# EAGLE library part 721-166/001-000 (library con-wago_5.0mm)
Serie 721, Stiftleiste mit geraden Einlötstiften / Series 721, Male connector with straight solder pins Polzahl / Pole No.: 6 Rastermaß / Pitch: 5 mm Bemessungsspannung / Rated Voltage: 320 V Nennstrom / Nominal Current: 16 A Lötstiftlänge: / Solder Pin Length: 5 mm Farbe / Color: lichtgrau / light gray Stand: 01.01.2012. Die jeweils aktuellen Daten zu diesem Artikel finden Sie in unserem Produktkatalog, den Sie unter www.wago.com einsehen können. As of: 01/01/2012. Please find the newest data for this article in our product catalogue, which can be viewed under www.wago.com.

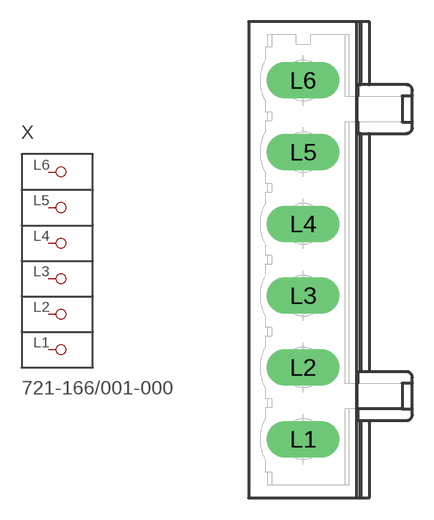
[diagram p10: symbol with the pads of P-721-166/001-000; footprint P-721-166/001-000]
Designator prefix X

## 721-166/001-000  [P-721-166/001-000]
L1  P1
L2  P2
L3  P3
L4  P4
L5  P5
L6  P6

## Footprint P-721-166/001-000 (pad centres in mm)
drill 1.7 long: L1 -1.9,-12.5; L2 -1.9,-7.5; L3 -1.9,-2.5; L4 -1.9,2.5; L5 -1.9,7.5; L6 -1.9,12.5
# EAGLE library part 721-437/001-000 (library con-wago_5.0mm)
Serie 721, Stiftleiste mit abgewinkelten Einlötstiften / Series 721, Male connector with angled solder pins Polzahl / Pole No.: 7 Rastermaß / Pitch: 5 mm Bemessungsspannung / Rated Voltage: 320 V Nennstrom / Nominal Current: 12 A Lötstiftlänge: / Solder Pin Length: 3.8 mm Farbe / Color: lichtgrau / light gray Stand: 01.01.2012. Die jeweils aktuellen Daten zu diesem Artikel finden Sie in unserem Produktkatalog, den Sie unter www.wago.com einsehen können. As of: 01/01/2012. Please find the newest data for this article in our product catalogue, which can be viewed under www.wago.com.

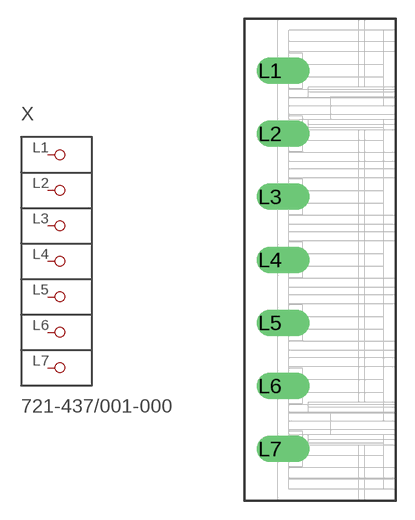
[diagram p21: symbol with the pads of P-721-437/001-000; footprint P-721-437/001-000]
Designator prefix X

## 721-437/001-000  [P-721-437/001-000]
L1  P1
L2  P2
L3  P3
L4  P4
L5  P5
L6  P6
L7  P7

## Footprint P-721-437/001-000 (pad centres in mm)
drill 1.4 offset: L1 -4,15; L2 -4,10; L3 -4,5; L4 -4,0; L5 -4,-5; L6 -4,-10; L7 -4,-15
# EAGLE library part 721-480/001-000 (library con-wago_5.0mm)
Serie 721, Stiftleiste mit abgewinkelten Einlötstiften / Series 721, Male connector with angled solder pins Polzahl / Pole No.: 20 Rastermaß / Pitch: 5 mm Bemessungsspannung / Rated Voltage: 320 V Nennstrom / Nominal Current: 16 A Lötstiftlänge: / Solder Pin Length: 3.8 mm Farbe / Color: lichtgrau / light gray Stand: 01.01.2012. Die jeweils aktuellen Daten zu diesem Artikel finden Sie in unserem Produktkatalog, den Sie unter www.wago.com einsehen können. As of: 01/01/2012. Please find the newest data for this article in our product catalogue, which can be viewed under www.wago.com.

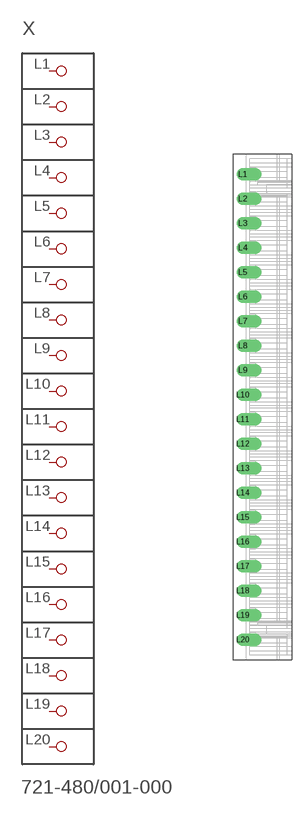
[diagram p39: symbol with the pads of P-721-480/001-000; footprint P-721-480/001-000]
Designator prefix X

## 721-480/001-000  [P-721-480/001-000]
L1  P1
L2  P2
L3  P3
L4  P4
L5  P5
L6  P6
L7  P7
L8  P8
L9  P9
L10  P10
L11  P11
L12  P12
L13  P13
L14  P14
L15  P15
L16  P16
L17  P17
L18  P18
L19  P19
L20  P20

## Footprint P-721-480/001-000 (pad centres in mm)
drill 1.7 offset: L1 -4,47.5; L2 -4,42.5; L3 -4,37.5; L4 -4,32.5; L5 -4,27.5; L6 -4,22.5; L7 -4,17.5; L8 -4,12.5; L9 -4,7.5; L10 -4,2.5; L11 -4,-2.5; L12 -4,-7.5; L13 -4,-12.5; L14 -4,-17.5; L15 -4,-22.5; L16 -4,-27.5; L17 -4,-32.5; L18 -4,-37.5; L19 -4,-42.5; L20 -4,-47.5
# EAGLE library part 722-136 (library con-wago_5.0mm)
Serie 722, Federleiste mit geraden Einlötstiften / Series 722, Female connector with straight solder pins Polzahl / Pole No.: 6 Rastermaß / Pitch: 5 mm Bemessungsspannung / Rated Voltage: 320 V Nennstrom / Nominal Current: 12 A Lötstiftlänge: / Solder Pin Length: 5 mm Farbe / Color: lichtgrau / light gray Stand: 01.01.2012. Die jeweils aktuellen Daten zu diesem Artikel finden Sie in unserem Produktkatalog, den Sie unter www.wago.com einsehen können. As of: 01/01/2012. Please find the newest data for this article in our product catalogue, which can be viewed under www.wago.com.

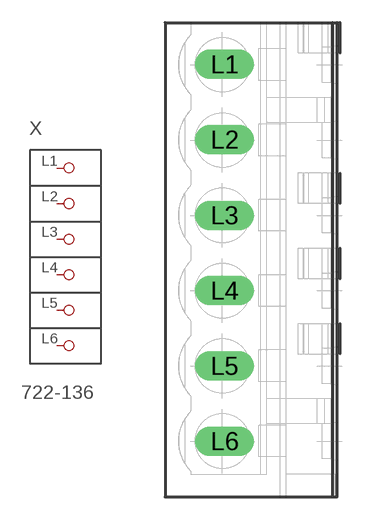
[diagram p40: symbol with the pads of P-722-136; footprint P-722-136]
Designator prefix X

## 722-136  [P-722-136]
L1  P1
L2  P2
L3  P3
L4  P4
L5  P5
L6  P6

## Footprint P-722-136 (pad centres in mm)
drill 1.3 long: L1 -1.923,12.975; L2 -1.923,7.975; L3 -1.923,2.95; L4 -1.923,-2.05; L5 -1.923,-7.05; L6 -1.923,-12.05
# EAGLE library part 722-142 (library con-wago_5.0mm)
Serie 722, Federleiste mit geraden Einlötstiften / Series 722, Female connector with straight solder pins Polzahl / Pole No.: 12 Rastermaß / Pitch: 5 mm Bemessungsspannung / Rated Voltage: 320 V Nennstrom / Nominal Current: 12 A Lötstiftlänge: / Solder Pin Length: 5 mm Farbe / Color: lichtgrau / light gray Stand: 01.01.2012. Die jeweils aktuellen Daten zu diesem Artikel finden Sie in unserem Produktkatalog, den Sie unter www.wago.com einsehen können. As of: 01/01/2012. Please find the newest data for this article in our product catalogue, which can be viewed under www.wago.com.

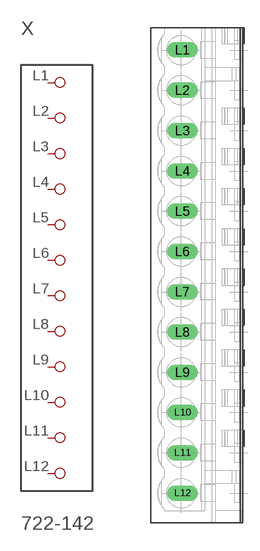
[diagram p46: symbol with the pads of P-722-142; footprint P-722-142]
Designator prefix X

## 722-142  [P-722-142]
L1  P1
L2  P2
L3  P3
L4  P4
L5  P5
L6  P6
L7  P7
L8  P8
L9  P9
L10  P10
L11  P11
L12  P12

## Footprint P-722-142 (pad centres in mm)
drill 1.3 long: L1 -2.068,27.975; L2 -2.068,22.975; L3 -2.068,17.95; L4 -2.068,12.95; L5 -2.068,7.95; L6 -2.068,2.95; L7 -2.068,-2.05; L8 -2.068,-7.05; L9 -2.068,-12.05; L10 -2.068,-17.05; L11 -2.068,-22.05; L12 -2.068,-27.05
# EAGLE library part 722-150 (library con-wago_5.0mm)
Serie 722, Federleiste mit geraden Einlötstiften / Series 722, Female connector with straight solder pins Polzahl / Pole No.: 20 Rastermaß / Pitch: 5 mm Bemessungsspannung / Rated Voltage: 320 V Nennstrom / Nominal Current: 12 A Lötstiftlänge: / Solder Pin Length: 5 mm Farbe / Color: lichtgrau / light gray Stand: 01.01.2012. Die jeweils aktuellen Daten zu diesem Artikel finden Sie in unserem Produktkatalog, den Sie unter www.wago.com einsehen können. As of: 01/01/2012. Please find the newest data for this article in our product catalogue, which can be viewed under www.wago.com.

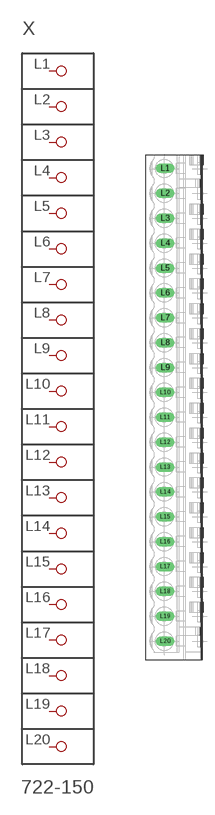
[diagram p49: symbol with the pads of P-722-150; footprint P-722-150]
Designator prefix X

## 722-150  [P-722-150]
L1  P1
L2  P2
L3  P3
L4  P4
L5  P5
L6  P6
L7  P7
L8  P8
L9  P9
L10  P10
L11  P11
L12  P12
L13  P13
L14  P14
L15  P15
L16  P16
L17  P17
L18  P18
L19  P19
L20  P20

## Footprint P-722-150 (pad centres in mm)
drill 1.3 long: L1 -2.265,47.96; L2 -2.265,42.96; L3 -2.265,37.935; L4 -2.265,32.935; L5 -2.265,27.935; L6 -2.265,22.935; L7 -2.265,17.935; L8 -2.265,12.935; L9 -2.265,7.935; L10 -2.265,2.935; L11 -2.265,-2.065; L12 -2.265,-7.065; L13 -2.265,-12.065; L14 -2.265,-17.065; L15 -2.265,-22.065; L16 -2.265,-27.065; L17 -2.265,-32.065; L18 -2.265,-37.065; L19 -2.265,-42.065; L20 -2.265,-47.065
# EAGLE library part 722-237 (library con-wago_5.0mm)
Serie 722, Federleiste mit abgewinkelten Einlötstiften / Series 722, Female connector with angled solder pins Polzahl / Pole No.: 7 Rastermaß / Pitch: 5 mm Bemessungsspannung / Rated Voltage: 320 V Nennstrom / Nominal Current: 12 A Lötstiftlänge: / Solder Pin Length: 5 mm Farbe / Color: lichtgrau / light gray Stand: 01.01.2012. Die jeweils aktuellen Daten zu diesem Artikel finden Sie in unserem Produktkatalog, den Sie unter www.wago.com einsehen können. As of: 01/01/2012. Please find the newest data for this article in our product catalogue, which can be viewed under www.wago.com.

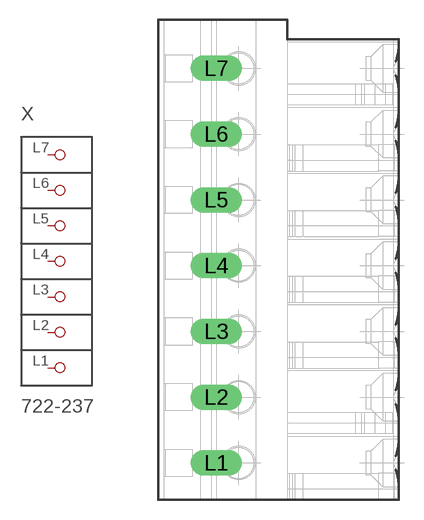
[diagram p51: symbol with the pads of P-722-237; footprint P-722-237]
Designator prefix X

## 722-237  [P-722-237]
L1  P1
L2  P2
L3  P3
L4  P4
L5  P5
L6  P6
L7  P7

## Footprint P-722-237 (pad centres in mm)
drill 1.3 long: L1 -4.939,-15.45; L2 -4.939,-10.45; L3 -4.939,-5.45; L4 -4.939,-0.45; L5 -4.939,4.55; L6 -4.939,9.55; L7 -4.939,14.55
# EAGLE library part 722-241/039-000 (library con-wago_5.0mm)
Serie 722, Federleiste mit Verriegelungsklinken / Series 722, Female connector with locking levers Polzahl / Pole No.: 11 Bemessungsspannung / Rated Voltage: 320 V Nennstrom / Nominal Current: 12 A Lötstiftlänge: / Solder Pin Length: 5 mm Farbe / Color: lichtgrau / light gray Stand: 01.01.2012. Die jeweils aktuellen Daten zu diesem Artikel finden Sie in unserem Produktkatalog, den Sie unter www.wago.com einsehen können. As of: 01/01/2012. Please find the newest data for this article in our product catalogue, which can be viewed under www.wago.com.

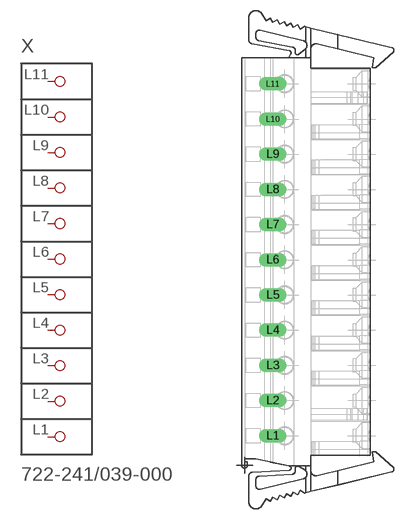
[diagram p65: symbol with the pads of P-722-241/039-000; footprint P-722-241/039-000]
Designator prefix X

## 722-241/039-000  [P-722-241/039-000]
L1  P1
L2  P2
L3  P3
L4  P4
L5  P5
L6  P6
L7  P7
L8  P8
L9  P9
L10  P10
L11  P11

## Footprint P-722-241/039-000 (pad centres in mm)
drill 1.3 long: L1 -6.03,-25; L2 -6.03,-20; L3 -6.03,-15; L4 -6.03,-10; L5 -6.03,-5; L6 -6.03,0; L7 -6.03,5; L8 -6.03,10; L9 -6.03,15; L10 -6.03,20; L11 -6.03,25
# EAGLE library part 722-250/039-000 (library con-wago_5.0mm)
Serie 722, Federleiste mit Verriegelungsklinken / Series 722, Female connector with locking levers Polzahl / Pole No.: 20 Lötstiftlänge: / Solder Pin Length: 5 mm Farbe / Color: lichtgrau / light gray Stand: 01.01.2012. Die jeweils aktuellen Daten zu diesem Artikel finden Sie in unserem Produktkatalog, den Sie unter www.wago.com einsehen können. As of: 01/01/2012. Please find the newest data for this article in our product catalogue, which can be viewed under www.wago.com.

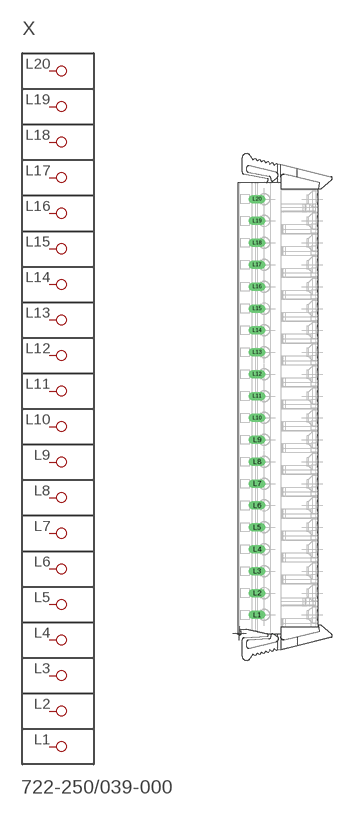
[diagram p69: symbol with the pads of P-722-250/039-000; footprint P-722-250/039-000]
Designator prefix X

## 722-250/039-000  [P-722-250/039-000]
L1  P1
L2  P2
L3  P3
L4  P4
L5  P5
L6  P6
L7  P7
L8  P8
L9  P9
L10  P10
L11  P11
L12  P12
L13  P13
L14  P14
L15  P15
L16  P16
L17  P17
L18  P18
L19  P19
L20  P20

## Footprint P-722-250/039-000 (pad centres in mm)
drill 1.3 long: L1 -5.811,-47.5; L2 -5.811,-42.5; L3 -5.811,-37.5; L4 -5.811,-32.5; L5 -5.811,-27.5; L6 -5.811,-22.5; L7 -5.811,-17.5; L8 -5.811,-12.5; L9 -5.811,-7.5; L10 -5.811,-2.5; L11 -5.811,2.5; L12 -5.811,7.5; L13 -5.811,12.5; L14 -5.811,17.5; L15 -5.811,22.5; L16 -5.811,27.5; L17 -5.811,32.5; L18 -5.811,37.5; L19 -5.811,42.5; L20 -5.811,47.5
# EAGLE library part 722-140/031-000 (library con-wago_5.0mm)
Serie 722, Federleiste mit Durchführungsflanschen / Series 722, Female connector with feedthrough flanges Polzahl / Pole No.: 10 Bemessungsspannung / Rated Voltage: 250 V Nennstrom / Nominal Current: 12 A Lötstiftlänge: / Solder Pin Length: 5 mm Farbe / Color: xxxx / xxxx Stand: 01.01.2012. Die jeweils aktuellen Daten zu diesem Artikel finden Sie in unserem Produktkatalog, den Sie unter www.wago.com einsehen können. As of: 01/01/2012. Please find the newest data for this article in our product catalogue, which can be viewed under www.wago.com.

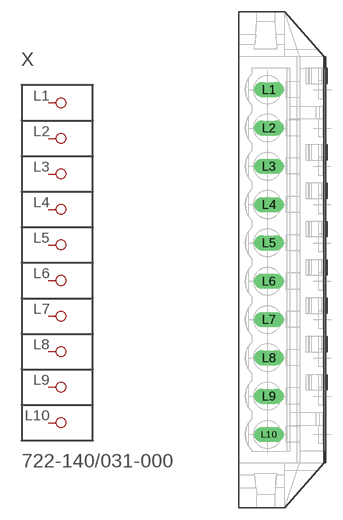
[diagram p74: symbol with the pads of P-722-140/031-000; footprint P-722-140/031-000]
Designator prefix X

## 722-140/031-000  [P-722-140/031-000]
L1  P1
L2  P2
L3  P3
L4  P4
L5  P5
L6  P6
L7  P7
L8  P8
L9  P9
L10  P10

## Footprint P-722-140/031-000 (pad centres in mm)
drill 1.3 long: L1 -2.085,22.2; L2 -2.085,17.2; L3 -2.085,12.2; L4 -2.085,7.2; L5 -2.085,2.2; L6 -2.085,-2.8; L7 -2.085,-7.8; L8 -2.085,-12.8; L9 -2.085,-17.8; L10 -2.085,-22.8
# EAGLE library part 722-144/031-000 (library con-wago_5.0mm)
Serie 722, Federleiste mit Durchführungsflanschen / Series 722, Female connector with feedthrough flanges Polzahl / Pole No.: 14 Bemessungsspannung / Rated Voltage: 250 V Nennstrom / Nominal Current: 12 A Lötstiftlänge: / Solder Pin Length: 5 mm Farbe / Color: xxxx / xxxx Stand: 01.01.2012. Die jeweils aktuellen Daten zu diesem Artikel finden Sie in unserem Produktkatalog, den Sie unter www.wago.com einsehen können. As of: 01/01/2012. Please find the newest data for this article in our product catalogue, which can be viewed under www.wago.com.

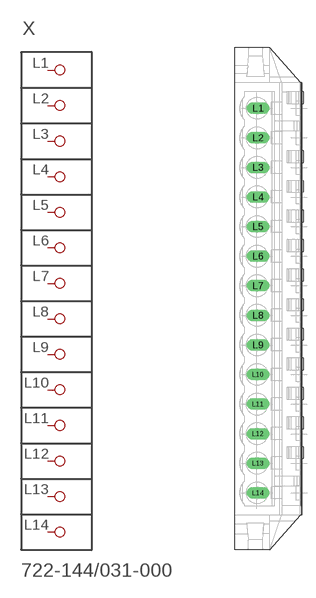
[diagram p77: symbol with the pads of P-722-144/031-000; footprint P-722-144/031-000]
Designator prefix X

## 722-144/031-000  [P-722-144/031-000]
L1  P1
L2  P2
L3  P3
L4  P4
L5  P5
L6  P6
L7  P7
L8  P8
L9  P9
L10  P10
L11  P11
L12  P12
L13  P13
L14  P14

## Footprint P-722-144/031-000 (pad centres in mm)
drill 1.3 long: L1 -2.182,32.2; L2 -2.182,27.2; L3 -2.182,22.2; L4 -2.182,17.2; L5 -2.182,12.2; L6 -2.182,7.2; L7 -2.182,2.2; L8 -2.182,-2.8; L9 -2.182,-7.8; L10 -2.182,-12.8; L11 -2.182,-17.8; L12 -2.182,-22.8; L13 -2.182,-27.8; L14 -2.182,-32.8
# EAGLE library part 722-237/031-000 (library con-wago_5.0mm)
Serie 722, Federleiste mit Durchführungsflanschen / Series 722, Female connector with feedthrough flanges Polzahl / Pole No.: 7 Rastermaß / Pitch: 5 mm Bemessungsspannung / Rated Voltage: 320 V Nennstrom / Nominal Current: 12 A Lötstiftlänge: / Solder Pin Length: 5 mm Farbe / Color: lichtgrau / light gray Stand: 01.01.2012. Die jeweils aktuellen Daten zu diesem Artikel finden Sie in unserem Produktkatalog, den Sie unter www.wago.com einsehen können. As of: 01/01/2012. Please find the newest data for this article in our product catalogue, which can be viewed under www.wago.com.

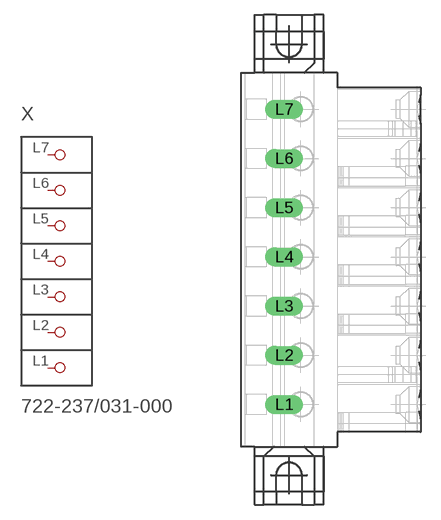
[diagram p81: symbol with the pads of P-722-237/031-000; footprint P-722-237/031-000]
Designator prefix X

## 722-237/031-000  [P-722-237/031-000]
L1  P1
L2  P2
L3  P3
L4  P4
L5  P5
L6  P6
L7  P7

## Footprint P-722-237/031-000 (pad centres in mm)
drill 1.3 long: L1 -4.995,-14.7; L2 -4.995,-9.7; L3 -4.995,-4.7; L4 -4.995,0.3; L5 -4.995,5.3; L6 -4.995,10.3; L7 -4.995,15.3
